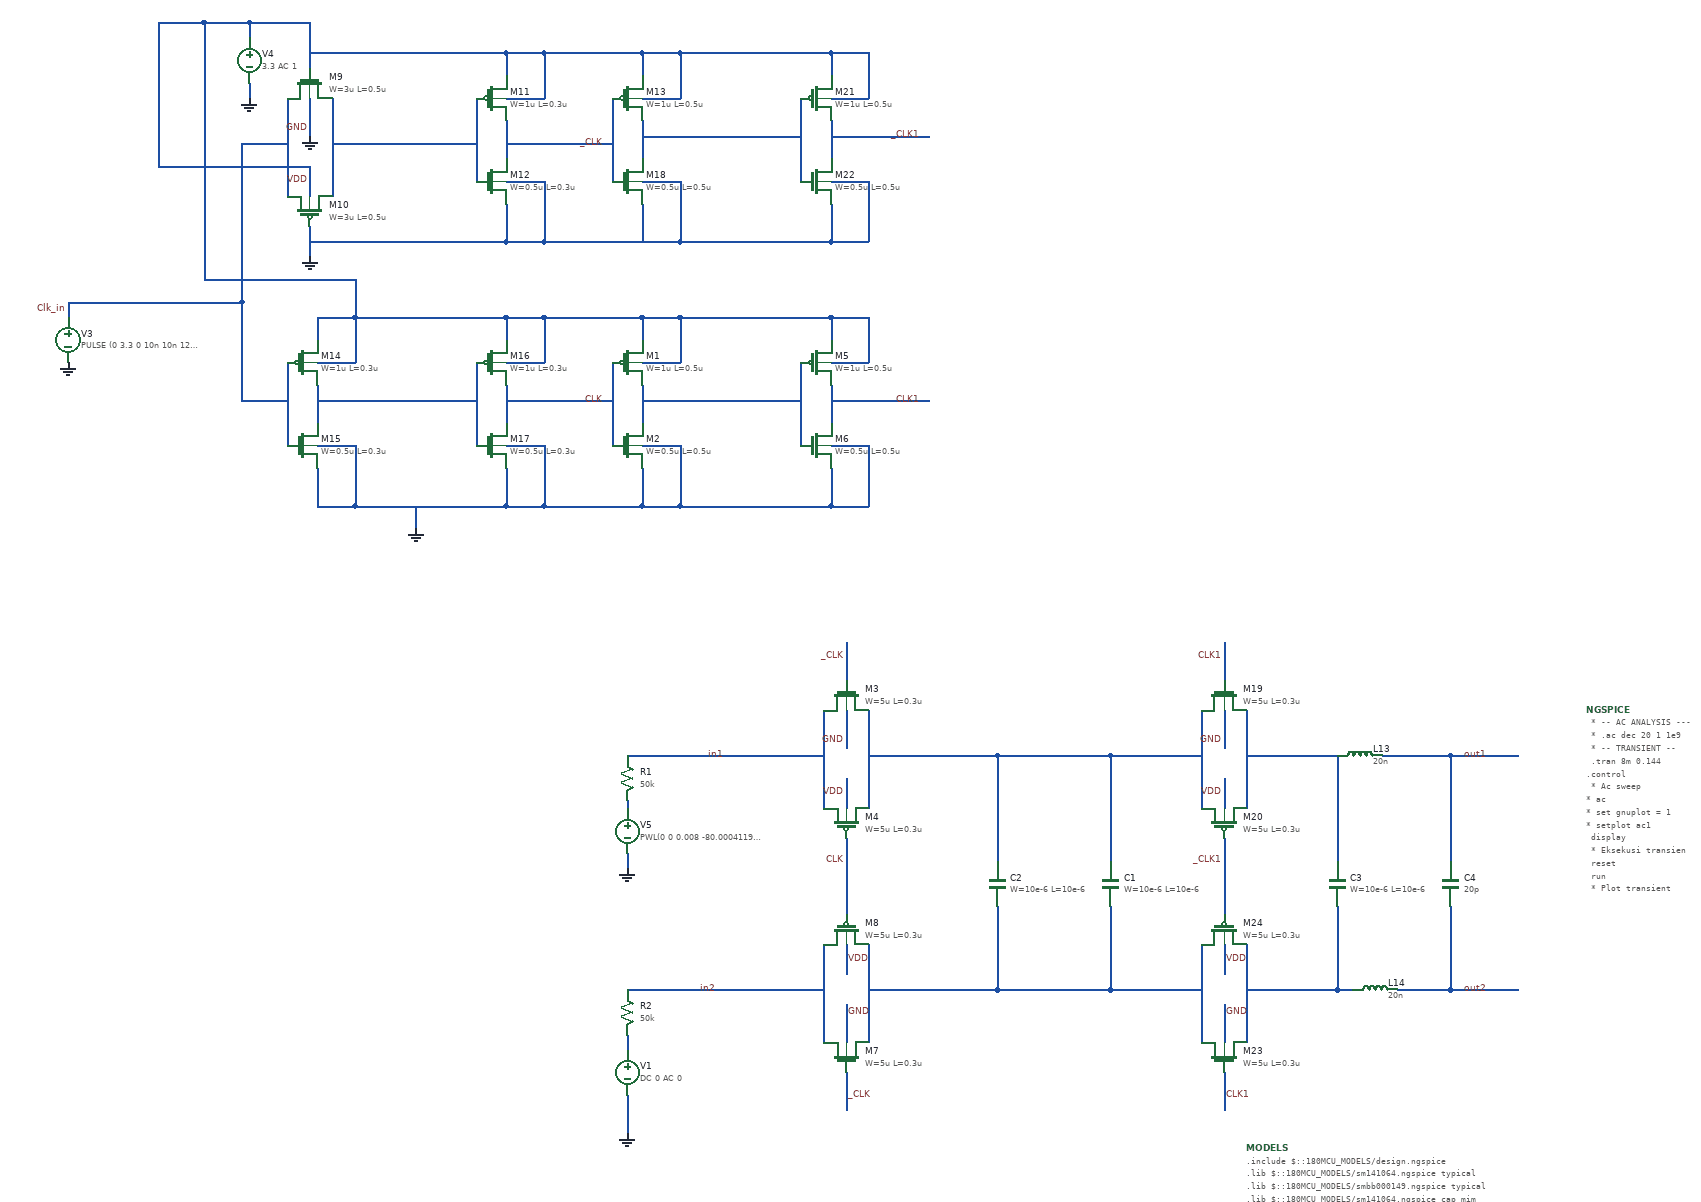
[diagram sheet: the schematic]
v {xschem version=3.4.7 file_version=1.2}
G {}
K {}
V {}
S {}
E {}
N 540 -1460 540 -1330 {lab=Clk_in}
N 600 -1460 600 -1330 {lab=#net1}
N 570 -1460 570 -1410 {lab=GND}
N 570 -1370 570 -1330 {lab=VDD}
N 570 -1290 570 -1250 {lab=GND}
N 570 -1560 570 -1500 {lab=VDD}
N 410 -1190 480 -1190 {lab=Clk_in}
N 480 -1400 480 -1190 {lab=Clk_in}
N 480 -1400 540 -1400 {lab=Clk_in}
N 790 -1460 790 -1350 {lab=#net1}
N 600 -1400 790 -1400 {lab=#net1}
N 830 -1430 830 -1370 {lab=_CLK}
N 830 -1400 970 -1400 {lab=_CLK}
N 570 -1520 630 -1520 {lab=VDD}
N 630 -1520 830 -1520 {lab=VDD}
N 830 -1520 830 -1490 {lab=VDD}
N 570 -1270 830 -1270 {lab=GND}
N 830 -1320 830 -1270 {lab=GND}
N 830 -1460 880 -1460 {lab=VDD}
N 880 -1520 880 -1460 {lab=VDD}
N 830 -1520 880 -1520 {lab=VDD}
N 830 -1350 880 -1350 {lab=GND}
N 880 -1350 880 -1270 {lab=GND}
N 830 -1270 870 -1270 {lab=GND}
N 870 -1270 880 -1270 {lab=GND}
N 540 -1110 540 -1000 {lab=Clk_in}
N 580 -1080 580 -1020 {lab=#net2}
N 580 -1170 580 -1140 {lab=VDD}
N 580 -970 580 -920 {lab=GND}
N 580 -1110 630 -1110 {lab=VDD}
N 630 -1170 630 -1110 {lab=VDD}
N 580 -1170 630 -1170 {lab=VDD}
N 580 -1000 630 -1000 {lab=GND}
N 630 -1000 630 -920 {lab=GND}
N 580 -920 620 -920 {lab=GND}
N 620 -920 630 -920 {lab=GND}
N 480 -1190 480 -1060 {lab=Clk_in}
N 480 -1060 540 -1060 {lab=Clk_in}
N 790 -1110 790 -1000 {lab=#net2}
N 830 -1080 830 -1020 {lab=CLK}
N 830 -1170 830 -1140 {lab=VDD}
N 830 -970 830 -920 {lab=GND}
N 830 -1110 880 -1110 {lab=VDD}
N 880 -1170 880 -1110 {lab=VDD}
N 830 -1170 880 -1170 {lab=VDD}
N 830 -1000 880 -1000 {lab=GND}
N 880 -1000 880 -920 {lab=GND}
N 830 -920 870 -920 {lab=GND}
N 870 -920 880 -920 {lab=GND}
N 580 -1060 790 -1060 {lab=#net2}
N 830 -1060 970 -1060 {lab=CLK}
N 630 -1170 830 -1170 {lab=VDD}
N 630 -920 830 -920 {lab=GND}
N 250 -1190 250 -1170 {lab=Clk_in}
N 490 -1560 570 -1560 {lab=VDD}
N 490 -1480 490 -1460 {lab=GND}
N 630 -1220 630 -1170 {lab=VDD}
N 430 -1220 630 -1220 {lab=VDD}
N 430 -1560 430 -1220 {lab=VDD}
N 430 -1560 490 -1560 {lab=VDD}
N 490 -1560 490 -1540 {lab=VDD}
N 370 -1370 570 -1370 {lab=VDD}
N 370 -1560 370 -1370 {lab=VDD}
N 370 -1560 430 -1560 {lab=VDD}
N 710 -920 710 -890 {lab=GND}
N 1150 -590 1250 -590 {lab=in1}
N 1250 -650 1250 -520 {lab=in1}
N 1310 -650 1310 -520 {lab=#net3}
N 1280 -650 1280 -600 {lab=GND}
N 1280 -560 1280 -520 {lab=VDD}
N 1280 -740 1280 -690 {lab=_CLK}
N 1280 -480 1280 -420 {lab=CLK}
N 1310 -590 1360 -590 {lab=#net3}
N 1310 -340 1310 -210 {lab=#net4}
N 1250 -340 1250 -210 {lab=in2}
N 1280 -260 1280 -210 {lab=GND}
N 1280 -340 1280 -300 {lab=VDD}
N 1280 -170 1280 -120 {lab=_CLK}
N 1280 -420 1280 -380 {lab=CLK}
N 1150 -280 1250 -280 {lab=in2}
N 1310 -280 1360 -280 {lab=#net4}
N 990 -590 1150 -590 {lab=in1}
N 990 -280 1150 -280 {lab=in2}
N 1360 -590 1480 -590 {lab=#net3}
N 1360 -280 1480 -280 {lab=#net4}
N 1480 -280 1630 -280 {lab=#net4}
N 1480 -590 1630 -590 {lab=#net3}
N 1750 -650 1750 -520 {lab=#net3}
N 1810 -650 1810 -520 {lab=#net5}
N 1780 -650 1780 -600 {lab=GND}
N 1780 -560 1780 -520 {lab=VDD}
N 1780 -740 1780 -690 {lab=CLK1}
N 1780 -480 1780 -420 {lab=_CLK1}
N 1810 -590 1860 -590 {lab=#net5}
N 1810 -340 1810 -210 {lab=#net6}
N 1750 -340 1750 -210 {lab=#net4}
N 1780 -260 1780 -210 {lab=GND}
N 1780 -340 1780 -300 {lab=VDD}
N 1780 -170 1780 -120 {lab=CLK1}
N 1780 -420 1780 -380 {lab=_CLK1}
N 1630 -590 1750 -590 {lab=#net3}
N 1630 -280 1750 -280 {lab=#net4}
N 1860 -590 1930 -590 {lab=#net5}
N 1810 -280 1850 -280 {lab=#net6}
N 2080 -590 2170 -590 {lab=out1}
N 990 -460 990 -440 {lab=GND}
N 970 -1110 970 -1000 {lab=CLK}
N 1010 -1080 1010 -1020 {lab=#net7}
N 1010 -1170 1010 -1140 {lab=VDD}
N 1010 -970 1010 -920 {lab=GND}
N 1010 -1110 1060 -1110 {lab=VDD}
N 1060 -1170 1060 -1110 {lab=VDD}
N 1010 -1170 1060 -1170 {lab=VDD}
N 1010 -1000 1060 -1000 {lab=GND}
N 1060 -1000 1060 -920 {lab=GND}
N 1010 -920 1050 -920 {lab=GND}
N 1050 -920 1060 -920 {lab=GND}
N 1220 -1110 1220 -1000 {lab=#net7}
N 1260 -1080 1260 -1020 {lab=CLK1}
N 1260 -1170 1260 -1140 {lab=VDD}
N 1260 -970 1260 -920 {lab=GND}
N 1260 -1110 1310 -1110 {lab=VDD}
N 1310 -1170 1310 -1110 {lab=VDD}
N 1260 -1170 1310 -1170 {lab=VDD}
N 1260 -1000 1310 -1000 {lab=GND}
N 1310 -1000 1310 -920 {lab=GND}
N 1260 -920 1300 -920 {lab=GND}
N 1300 -920 1310 -920 {lab=GND}
N 1010 -1060 1220 -1060 {lab=#net7}
N 1060 -1170 1260 -1170 {lab=VDD}
N 1060 -920 1260 -920 {lab=GND}
N 1260 -1060 1390 -1060 {lab=CLK1}
N 970 -1460 970 -1350 {lab=_CLK}
N 1010 -1430 1010 -1370 {lab=#net8}
N 1010 -1520 1010 -1490 {lab=VDD}
N 1010 -1320 1010 -1270 {lab=GND}
N 1010 -1460 1060 -1460 {lab=VDD}
N 1060 -1520 1060 -1460 {lab=VDD}
N 1010 -1520 1060 -1520 {lab=VDD}
N 1010 -1350 1060 -1350 {lab=GND}
N 1060 -1350 1060 -1270 {lab=GND}
N 1010 -1270 1050 -1270 {lab=GND}
N 1050 -1270 1060 -1270 {lab=GND}
N 1220 -1460 1220 -1350 {lab=#net8}
N 1260 -1430 1260 -1370 {lab=_CLK1}
N 1260 -1520 1260 -1490 {lab=VDD}
N 1260 -1320 1260 -1270 {lab=GND}
N 1260 -1460 1310 -1460 {lab=VDD}
N 1310 -1520 1310 -1460 {lab=VDD}
N 1260 -1520 1310 -1520 {lab=VDD}
N 1260 -1350 1310 -1350 {lab=GND}
N 1310 -1350 1310 -1270 {lab=GND}
N 1260 -1270 1300 -1270 {lab=GND}
N 1300 -1270 1310 -1270 {lab=GND}
N 1010 -1410 1220 -1410 {lab=#net8}
N 1060 -1520 1260 -1520 {lab=VDD}
N 1060 -1270 1260 -1270 {lab=GND}
N 1260 -1410 1390 -1410 {lab=_CLK1}
N 880 -1520 1010 -1520 {lab=VDD}
N 880 -1270 1020 -1270 {lab=GND}
N 880 -1170 1010 -1170 {lab=VDD}
N 880 -920 1010 -920 {lab=GND}
N 250 -1190 350 -1190 {lab=Clk_in}
N 350 -1190 410 -1190 {lab=Clk_in}
N 1930 -490 1930 -450 {lab=#net5}
N 2080 -590 2080 -550 {lab=out1}
N 1930 -590 1930 -550 {lab=#net5}
N 1480 -480 1480 -450 {lab=#net3}
N 1630 -480 1630 -450 {lab=#net3}
N 990 -140 990 -90 {lab=GND}
N 1480 -590 1480 -540 {lab=#net3}
N 1630 -590 1630 -540 {lab=#net3}
N 1480 -390 1480 -360 {lab=#net4}
N 1630 -390 1630 -360 {lab=#net4}
N 1480 -300 1480 -280 {lab=#net4}
N 1630 -300 1630 -280 {lab=#net4}
N 1930 -390 1930 -350 {lab=#net6}
N 1930 -290 1930 -280 {lab=#net6}
N 2130 -280 2170 -280 {lab=out2}
N 2080 -490 2080 -450 {lab=out1}
N 2080 -390 2080 -350 {lab=out2}
N 2080 -290 2080 -280 {lab=out2}
N 1930 -550 1930 -490 {lab=#net5}
N 2080 -550 2080 -490 {lab=out1}
N 1850 -280 1930 -280 {lab=#net6}
N 2080 -280 2130 -280 {lab=out2}
N 1930 -350 1930 -290 {lab=#net6}
N 2080 -350 2080 -290 {lab=out2}
N 1630 -360 1630 -300 {lab=#net4}
N 1480 -360 1480 -300 {lab=#net4}
N 1480 -540 1480 -480 {lab=#net3}
N 1630 -540 1630 -480 {lab=#net3}
N 990 -530 990 -520 {lab=#net9}
N 990 -220 990 -200 {lab=#net10}
N 1990 -590 2080 -590 {lab=out1}
N 1930 -280 1950 -280 {lab=#net6}
N 2010 -280 2080 -280 {lab=out2}
C {symbols/nfet_03v3.sym} 570 -1480 1 0 {name=M9
L=0.5u
W=3u
nf=5
m=1
ad="'int((nf+1)/2) * W/nf * 0.18u'"
pd="'2*int((nf+1)/2) * (W/nf + 0.18u)'"
as="'int((nf+2)/2) * W/nf * 0.18u'"
ps="'2*int((nf+2)/2) * (W/nf + 0.18u)'"
nrd="'0.18u / W'" nrs="'0.18u / W'"
sa=0 sb=0 sd=0
model=nfet_03v3
spiceprefix=X
}
C {symbols/pfet_03v3.sym} 570 -1310 1 1 {name=M10
L=0.5u
W=3u
nf=5
m=1
ad="'int((nf+1)/2) * W/nf * 0.18u'"
pd="'2*int((nf+1)/2) * (W/nf + 0.18u)'"
as="'int((nf+2)/2) * W/nf * 0.18u'"
ps="'2*int((nf+2)/2) * (W/nf + 0.18u)'"
nrd="'0.18u / W'" nrs="'0.18u / W'"
sa=0 sb=0 sd=0
model=pfet_03v3
spiceprefix=X
}
C {lab_wire.sym} 570 -1420 0 0 {name=p20 sig_type=std_logic lab=GND}
C {lab_wire.sym} 570 -1350 0 0 {name=p21 sig_type=std_logic lab=VDD}
C {symbols/pfet_03v3.sym} 810 -1460 0 0 {name=M11
L=0.3u
W=1u
nf=1
m=1
ad="'int((nf+1)/2) * W/nf * 0.18u'"
pd="'2*int((nf+1)/2) * (W/nf + 0.18u)'"
as="'int((nf+2)/2) * W/nf * 0.18u'"
ps="'2*int((nf+2)/2) * (W/nf + 0.18u)'"
nrd="'0.18u / W'" nrs="'0.18u / W'"
sa=0 sb=0 sd=0
model=pfet_03v3
spiceprefix=X
}
C {symbols/nfet_03v3.sym} 810 -1350 0 0 {name=M12
L=0.3u
W=0.5u
nf=1
m=1
ad="'int((nf+1)/2) * W/nf * 0.18u'"
pd="'2*int((nf+1)/2) * (W/nf + 0.18u)'"
as="'int((nf+2)/2) * W/nf * 0.18u'"
ps="'2*int((nf+2)/2) * (W/nf + 0.18u)'"
nrd="'0.18u / W'" nrs="'0.18u / W'"
sa=0 sb=0 sd=0
model=nfet_03v3
spiceprefix=X
}
C {lab_wire.sym} 960 -1060 0 0 {name=p24 sig_type=std_logic lab=CLK}
C {lab_wire.sym} 960 -1400 0 0 {name=p25 sig_type=std_logic lab=_CLK}
C {symbols/pfet_03v3.sym} 560 -1110 0 0 {name=M14
L=0.3u
W=1u
nf=1
m=1
ad="'int((nf+1)/2) * W/nf * 0.18u'"
pd="'2*int((nf+1)/2) * (W/nf + 0.18u)'"
as="'int((nf+2)/2) * W/nf * 0.18u'"
ps="'2*int((nf+2)/2) * (W/nf + 0.18u)'"
nrd="'0.18u / W'" nrs="'0.18u / W'"
sa=0 sb=0 sd=0
model=pfet_03v3
spiceprefix=X
}
C {symbols/nfet_03v3.sym} 560 -1000 0 0 {name=M15
L=0.3u
W=0.5u
nf=1
m=1
ad="'int((nf+1)/2) * W/nf * 0.18u'"
pd="'2*int((nf+1)/2) * (W/nf + 0.18u)'"
as="'int((nf+2)/2) * W/nf * 0.18u'"
ps="'2*int((nf+2)/2) * (W/nf + 0.18u)'"
nrd="'0.18u / W'" nrs="'0.18u / W'"
sa=0 sb=0 sd=0
model=nfet_03v3
spiceprefix=X
}
C {symbols/pfet_03v3.sym} 810 -1110 0 0 {name=M16
L=0.3u
W=1u
nf=1
m=1
ad="'int((nf+1)/2) * W/nf * 0.18u'"
pd="'2*int((nf+1)/2) * (W/nf + 0.18u)'"
as="'int((nf+2)/2) * W/nf * 0.18u'"
ps="'2*int((nf+2)/2) * (W/nf + 0.18u)'"
nrd="'0.18u / W'" nrs="'0.18u / W'"
sa=0 sb=0 sd=0
model=pfet_03v3
spiceprefix=X
}
C {symbols/nfet_03v3.sym} 810 -1000 0 0 {name=M17
L=0.3u
W=0.5u
nf=1
m=1
ad="'int((nf+1)/2) * W/nf * 0.18u'"
pd="'2*int((nf+1)/2) * (W/nf + 0.18u)'"
as="'int((nf+2)/2) * W/nf * 0.18u'"
ps="'2*int((nf+2)/2) * (W/nf + 0.18u)'"
nrd="'0.18u / W'" nrs="'0.18u / W'"
sa=0 sb=0 sd=0
model=nfet_03v3
spiceprefix=X
}
C {vsource.sym} 250 -1140 0 0 {name=V3 value="PULSE (0 3.3 0 10n 10n 125n 250n) AC 0" savecurrent=false}
C {gnd.sym} 250 -1110 0 0 {name=l2 lab=GND}
C {lab_wire.sym} 250 -1180 0 0 {name=p23 sig_type=std_logic lab=Clk_in}
C {noconn.sym} 970 -1400 2 0 {name=l3}
C {noconn.sym} 970 -1060 2 0 {name=l4}
C {vsource.sym} 490 -1510 0 0 {name=V4 value="3.3 AC 1" savecurrent=false}
C {gnd.sym} 490 -1460 0 0 {name=l6 lab=GND}
C {gnd.sym} 570 -1250 0 0 {name=l7 lab=GND}
C {gnd.sym} 570 -1410 0 0 {name=l8 lab=GND}
C {gnd.sym} 710 -890 0 0 {name=l9 lab=GND}
C {symbols/nfet_03v3.sym} 1280 -670 1 0 {name=M3
L=0.3u
W=5u
nf=3
m=1
ad="'int((nf+1)/2) * W/nf * 0.18u'"
pd="'2*int((nf+1)/2) * (W/nf + 0.18u)'"
as="'int((nf+2)/2) * W/nf * 0.18u'"
ps="'2*int((nf+2)/2) * (W/nf + 0.18u)'"
nrd="'0.18u / W'" nrs="'0.18u / W'"
sa=0 sb=0 sd=0
model=nfet_03v3
spiceprefix=X
}
C {symbols/pfet_03v3.sym} 1280 -500 3 0 {name=M4
L=0.3u
W=5u
nf=3
m=1
ad="'int((nf+1)/2) * W/nf * 0.18u'"
pd="'2*int((nf+1)/2) * (W/nf + 0.18u)'"
as="'int((nf+2)/2) * W/nf * 0.18u'"
ps="'2*int((nf+2)/2) * (W/nf + 0.18u)'"
nrd="'0.18u / W'" nrs="'0.18u / W'"
sa=0 sb=0 sd=0
model=pfet_03v3
spiceprefix=X
}
C {lab_wire.sym} 1280 -610 0 0 {name=p6 sig_type=std_logic lab=GND
nf=1
L=0.3u
m=1
W=4u}
C {lab_wire.sym} 1280 -540 0 0 {name=p7 sig_type=std_logic lab=VDD
nf=1
L=0.3u
m=1
W=4u}
C {lab_wire.sym} 1280 -720 0 0 {name=p8 sig_type=std_logic lab=_CLK}
C {lab_wire.sym} 1280 -450 0 0 {name=p9 sig_type=std_logic lab=CLK
L=0.3u
nf=1
m=5
W=4u}
C {symbols/nfet_03v3.sym} 1280 -190 3 0 {name=M7
L=0.3u
W=5u
nf=3
m=1
ad="'int((nf+1)/2) * W/nf * 0.18u'"
pd="'2*int((nf+1)/2) * (W/nf + 0.18u)'"
as="'int((nf+2)/2) * W/nf * 0.18u'"
ps="'2*int((nf+2)/2) * (W/nf + 0.18u)'"
nrd="'0.18u / W'" nrs="'0.18u / W'"
sa=0 sb=0 sd=0
model=nfet_03v3
spiceprefix=X
}
C {symbols/pfet_03v3.sym} 1280 -360 1 0 {name=M8
L=0.3u
W=5u
nf=3
m=1
ad="'int((nf+1)/2) * W/nf * 0.18u'"
pd="'2*int((nf+1)/2) * (W/nf + 0.18u)'"
as="'int((nf+2)/2) * W/nf * 0.18u'"
ps="'2*int((nf+2)/2) * (W/nf + 0.18u)'"
nrd="'0.18u / W'" nrs="'0.18u / W'"
sa=0 sb=0 sd=0
model=pfet_03v3
spiceprefix=X
}
C {lab_wire.sym} 1280 -250 2 0 {name=p14 sig_type=std_logic lab=GND
nf=1
L=0.3u
m=1
W=4u}
C {lab_wire.sym} 1280 -320 2 0 {name=p15 sig_type=std_logic lab=VDD
nf=1
L=0.3u
m=1
W=4u}
C {lab_wire.sym} 1280 -140 2 0 {name=p16 sig_type=std_logic lab=_CLK
W=4u}
C {vsource.sym} 990 -170 0 0 {name=V1 value="DC 0 AC 0" savecurrent=false}
C {gnd.sym} 990 -90 0 0 {name=l1 lab=GND}
C {lab_wire.sym} 1120 -590 0 0 {name=p1 sig_type=std_logic lab=in1}
C {lab_wire.sym} 1110 -280 0 0 {name=p17 sig_type=std_logic lab=in2}
C {symbols/nfet_03v3.sym} 1780 -670 1 0 {name=M19
L=0.3u
W=5u
nf=3
m=1
ad="'int((nf+1)/2) * W/nf * 0.18u'"
pd="'2*int((nf+1)/2) * (W/nf + 0.18u)'"
as="'int((nf+2)/2) * W/nf * 0.18u'"
ps="'2*int((nf+2)/2) * (W/nf + 0.18u)'"
nrd="'0.18u / W'" nrs="'0.18u / W'"
sa=0 sb=0 sd=0
model=nfet_03v3
spiceprefix=X
}
C {symbols/pfet_03v3.sym} 1780 -500 3 0 {name=M20
L=0.3u
W=5u
nf=3
m=1
ad="'int((nf+1)/2) * W/nf * 0.18u'"
pd="'2*int((nf+1)/2) * (W/nf + 0.18u)'"
as="'int((nf+2)/2) * W/nf * 0.18u'"
ps="'2*int((nf+2)/2) * (W/nf + 0.18u)'"
nrd="'0.18u / W'" nrs="'0.18u / W'"
sa=0 sb=0 sd=0
model=pfet_03v3
spiceprefix=X
}
C {lab_wire.sym} 1780 -610 0 0 {name=p26 sig_type=std_logic lab=GND
nf=1
L=0.3u
m=1
W=4u}
C {lab_wire.sym} 1780 -540 0 0 {name=p27 sig_type=std_logic lab=VDD
nf=1
L=0.3u
m=1
W=4u}
C {lab_wire.sym} 1780 -720 0 0 {name=p28 sig_type=std_logic lab=CLK1
W=4u}
C {lab_wire.sym} 1780 -450 0 0 {name=p29 sig_type=std_logic lab=_CLK1
L=0.3u
nf=1
m=5
W=4u}
C {symbols/nfet_03v3.sym} 1780 -190 3 0 {name=M23
L=0.3u
W=5u
nf=3
m=1
ad="'int((nf+1)/2) * W/nf * 0.18u'"
pd="'2*int((nf+1)/2) * (W/nf + 0.18u)'"
as="'int((nf+2)/2) * W/nf * 0.18u'"
ps="'2*int((nf+2)/2) * (W/nf + 0.18u)'"
nrd="'0.18u / W'" nrs="'0.18u / W'"
sa=0 sb=0 sd=0
model=nfet_03v3
spiceprefix=X
}
C {symbols/pfet_03v3.sym} 1780 -360 1 0 {name=M24
L=0.3u
W=5u
nf=3
m=1
ad="'int((nf+1)/2) * W/nf * 0.18u'"
pd="'2*int((nf+1)/2) * (W/nf + 0.18u)'"
as="'int((nf+2)/2) * W/nf * 0.18u'"
ps="'2*int((nf+2)/2) * (W/nf + 0.18u)'"
nrd="'0.18u / W'" nrs="'0.18u / W'"
sa=0 sb=0 sd=0
model=pfet_03v3
spiceprefix=X
}
C {lab_wire.sym} 1780 -250 2 0 {name=p34 sig_type=std_logic lab=GND
nf=1
L=0.3u
m=1
W=4u}
C {lab_wire.sym} 1780 -320 2 0 {name=p35 sig_type=std_logic lab=VDD
nf=1
L=0.3u
m=1
W=4u}
C {lab_wire.sym} 1780 -140 2 0 {name=p36 sig_type=std_logic lab=CLK1
W=4u}
C {noconn.sym} 2170 -590 2 0 {name=l10}
C {noconn.sym} 2170 -280 2 0 {name=l11}
C {lab_wire.sym} 2130 -590 1 0 {name=p30 sig_type=std_logic lab=out1}
C {lab_wire.sym} 2130 -280 3 0 {name=p37 sig_type=std_logic lab=out2}
C {devices/code_shown.sym} 2260 -650 0 0 {name=NGSPICE only_toplevel=true
value="
	* -- AC ANALYSIS ---
	* .ac dec 20 1 1e9
	* -- TRANSIENT --
	.tran 8m 0.144
.control
	* Ac sweep
*	ac
*	set gnuplot = 1
*	setplot ac1
	display
	
	* Eksekusi transien
	reset
	run

	* Plot transient
	plot V(in1)-V(in2) 
	plot V(out1)-V(out2)
	plot db((V(out1)-V(out2))/(V(in1)-V(in2)))
	*plot ph(V(out1)-V(out2))

*a %vd([1 0 2 0]) filesrc
*.model filesrc filesource (file="CH1_2.txt" amploffset=[0 0] amplscale=[1 1]
*+ timeoffset=0 timescale=1
*+ timerelative=false amplstep=false)

*plot V(filesrc)

save all

.endc
"}
C {devices/code_shown.sym} 1810 -70 0 0 {name=MODELS only_toplevel=true
format="tcleval( @value )"
value="
.include $::180MCU_MODELS/design.ngspice
.lib $::180MCU_MODELS/sm141064.ngspice typical
.lib $::180MCU_MODELS/smbb000149.ngspice typical
.lib $::180MCU_MODELS/sm141064.ngspice cap_mim
.lib $::180MCU_MODELS/sm141064.ngspice moscap_typical
.lib $::180MCU_MODELS/sm141064.ngspice mimcap_typical
"}
C {gnd.sym} 990 -440 0 0 {name=l12 lab=GND}
C {symbols/pfet_03v3.sym} 990 -1110 0 0 {name=M1
L=0.5u
W=1u
nf=2
m=1
ad="'int((nf+1)/2) * W/nf * 0.18u'"
pd="'2*int((nf+1)/2) * (W/nf + 0.18u)'"
as="'int((nf+2)/2) * W/nf * 0.18u'"
ps="'2*int((nf+2)/2) * (W/nf + 0.18u)'"
nrd="'0.18u / W'" nrs="'0.18u / W'"
sa=0 sb=0 sd=0
model=pfet_03v3
spiceprefix=X
}
C {symbols/nfet_03v3.sym} 990 -1000 0 0 {name=M2
L=0.5u
W=0.5u
nf=1
m=1
ad="'int((nf+1)/2) * W/nf * 0.18u'"
pd="'2*int((nf+1)/2) * (W/nf + 0.18u)'"
as="'int((nf+2)/2) * W/nf * 0.18u'"
ps="'2*int((nf+2)/2) * (W/nf + 0.18u)'"
nrd="'0.18u / W'" nrs="'0.18u / W'"
sa=0 sb=0 sd=0
model=nfet_03v3
spiceprefix=X
}
C {symbols/pfet_03v3.sym} 1240 -1110 0 0 {name=M5
L=0.5u
W=1u
nf=2
m=1
ad="'int((nf+1)/2) * W/nf * 0.18u'"
pd="'2*int((nf+1)/2) * (W/nf + 0.18u)'"
as="'int((nf+2)/2) * W/nf * 0.18u'"
ps="'2*int((nf+2)/2) * (W/nf + 0.18u)'"
nrd="'0.18u / W'" nrs="'0.18u / W'"
sa=0 sb=0 sd=0
model=pfet_03v3
spiceprefix=X
}
C {symbols/nfet_03v3.sym} 1240 -1000 0 0 {name=M6
L=0.5u
W=0.5u
nf=1
m=1
ad="'int((nf+1)/2) * W/nf * 0.18u'"
pd="'2*int((nf+1)/2) * (W/nf + 0.18u)'"
as="'int((nf+2)/2) * W/nf * 0.18u'"
ps="'2*int((nf+2)/2) * (W/nf + 0.18u)'"
nrd="'0.18u / W'" nrs="'0.18u / W'"
sa=0 sb=0 sd=0
model=nfet_03v3
spiceprefix=X
}
C {lab_wire.sym} 1380 -1060 0 0 {name=p2 sig_type=std_logic lab=CLK1}
C {noconn.sym} 970 -1410 2 0 {name=l5}
C {symbols/pfet_03v3.sym} 990 -1460 0 0 {name=M13
L=0.5u
W=1u
nf=2
m=1
ad="'int((nf+1)/2) * W/nf * 0.18u'"
pd="'2*int((nf+1)/2) * (W/nf + 0.18u)'"
as="'int((nf+2)/2) * W/nf * 0.18u'"
ps="'2*int((nf+2)/2) * (W/nf + 0.18u)'"
nrd="'0.18u / W'" nrs="'0.18u / W'"
sa=0 sb=0 sd=0
model=pfet_03v3
spiceprefix=X
}
C {symbols/nfet_03v3.sym} 990 -1350 0 0 {name=M18
L=0.5u
W=0.5u
nf=1
m=1
ad="'int((nf+1)/2) * W/nf * 0.18u'"
pd="'2*int((nf+1)/2) * (W/nf + 0.18u)'"
as="'int((nf+2)/2) * W/nf * 0.18u'"
ps="'2*int((nf+2)/2) * (W/nf + 0.18u)'"
nrd="'0.18u / W'" nrs="'0.18u / W'"
sa=0 sb=0 sd=0
model=nfet_03v3
spiceprefix=X
}
C {symbols/pfet_03v3.sym} 1240 -1460 0 0 {name=M21
L=0.5u
W=1u
nf=2
m=1
ad="'int((nf+1)/2) * W/nf * 0.18u'"
pd="'2*int((nf+1)/2) * (W/nf + 0.18u)'"
as="'int((nf+2)/2) * W/nf * 0.18u'"
ps="'2*int((nf+2)/2) * (W/nf + 0.18u)'"
nrd="'0.18u / W'" nrs="'0.18u / W'"
sa=0 sb=0 sd=0
model=pfet_03v3
spiceprefix=X
}
C {symbols/nfet_03v3.sym} 1240 -1350 0 0 {name=M22
L=0.5u
W=0.5u
nf=1
m=1
ad="'int((nf+1)/2) * W/nf * 0.18u'"
pd="'2*int((nf+1)/2) * (W/nf + 0.18u)'"
as="'int((nf+2)/2) * W/nf * 0.18u'"
ps="'2*int((nf+2)/2) * (W/nf + 0.18u)'"
nrd="'0.18u / W'" nrs="'0.18u / W'"
sa=0 sb=0 sd=0
model=nfet_03v3
spiceprefix=X
}
C {lab_wire.sym} 1380 -1410 0 0 {name=p3 sig_type=std_logic lab=_CLK1}
C {symbols/cap_mim_1f0fF.sym} 1630 -420 0 0 {name=C1
W=10e-6
L=10e-6
model=cap_mim_2f0fF
spiceprefix=X
m=3}
C {symbols/cap_mim_1f0fF.sym} 1480 -420 0 0 {name=C2
W=10e-6
L=10e-6
model=cap_mim_2f0fF
spiceprefix=X
m=3}
C {symbols/cap_mim_1f0fF.sym} 1930 -420 0 0 {name=C3
W=10e-6
L=10e-6
model=cap_mim_2f0fF
spiceprefix=X
m=3}
C {vsource.sym} 990 -490 0 0 {name=V5 value="PWL(0 0 0.008	-80.00041199u 0.016	-133.086319u 0.024	85.89277649u 0.032	-94.17173767u 0.04	43.23672485u 0.048	10.87415981u 0.056	19.15146637u 0.064	13.92291355u 0.072	16.32160759u 0.08	4.195819378u 0.088	3.323663712u 0.096	8.602978706u 0.104	-7.884923935u 0.112	-14.38331318u 0.12	-10.79214478u 0.128	-8.228297234u 0.136	-7.73075819u 0.144	12.37324333u)" savecurrent=false}
C {res.sym} 990 -560 0 0 {name=R1
value=50k
footprint=1206
device=resistor
m=1}
C {res.sym} 990 -250 0 0 {name=R2
value=50k
footprint=1206
device=resistor
m=1}
C {ind.sym} 1960 -590 3 0 {name=L13
m=1
value=20n
footprint=1206
device=inductor}
C {capa.sym} 2080 -420 0 0 {name=C4
m=1
value=20p
footprint=1206
device="ceramic capacitor"}
C {ind.sym} 1980 -280 3 0 {name=L14
m=1
value=20n
footprint=1206
device=inductor}
